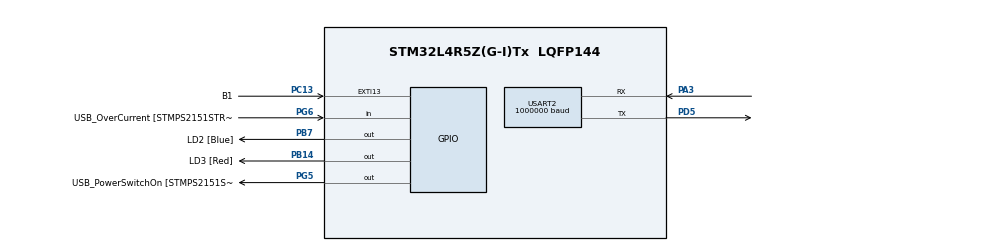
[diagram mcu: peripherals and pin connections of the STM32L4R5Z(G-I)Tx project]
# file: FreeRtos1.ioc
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FREERTOS.INCLUDE_vTaskDelayUntil=1
FREERTOS.Tasks01=defaultTask,0,128,StartDefaultTask,Default,NULL,Dynamic,NULL,NULL
FREERTOS.configTOTAL_HEAP_SIZE=15000
FREERTOS.configUSE_COUNTING_SEMAPHORES=1
FREERTOS.configUSE_RECURSIVE_MUTEXES=1
Mcu.Family=STM32L4
Mcu.Name=STM32L4R5Z(G-I)Tx
Mcu.Package=LQFP144
NVIC.PriorityGroup=NVIC_PRIORITYGROUP_4
NVIC.RCC_IRQn=true\:5\:0\:false\:false\:true\:true\:true
NVIC.TIM1_UP_TIM16_IRQn=true\:0\:0\:false\:false\:true\:false\:false
NVIC.TimeBase=TIM1_UP_TIM16_IRQn
NVIC.TimeBaseIP=TIM1
NVIC.USART2_IRQn=true\:5\:0\:false\:true\:true\:2\:true\:true
PA10.GPIO_Label=USB_ID
PA10.Signal=USB_OTG_FS_ID
PA11.GPIO_Label=USB_DM
PA11.Signal=USB_OTG_FS_DM
PA12.GPIO_Label=USB_DP
PA12.Signal=USB_OTG_FS_DP
PA13\ (JTMS/SWDIO).GPIO_Label=TMS
PA13\ (JTMS/SWDIO).Mode=Trace_Asynchronous_SW
PA13\ (JTMS/SWDIO).Signal=SYS_JTMS-SWDIO
PA14\ (JTCK/SWCLK).GPIO_Label=TCK
PA14\ (JTCK/SWCLK).Mode=Trace_Asynchronous_SW
PA14\ (JTCK/SWCLK).Signal=SYS_JTCK-SWCLK
PA3.GPIO_PuPd=GPIO_PULLUP
PA3.Mode=Asynchronous
PA3.Signal=USART2_RX
PA8.GPIO_Label=USB_SOF [TP1]
PA8.Signal=USB_OTG_FS_SOF
PA9.GPIO_Label=USB_VBUS
PA9.Signal=USB_OTG_FS_VBUS
PB14.GPIO_Label=LD3 [Red]
PB14.PinState=GPIO_PIN_SET
PB14.Signal=GPIO_Output
PB3\ (JTDO/TRACESWO).GPIO_Label=SWO
PB3\ (JTDO/TRACESWO).Mode=Trace_Asynchronous_SW
PB3\ (JTDO/TRACESWO).Signal=SYS_JTDO-SWO
PB7.GPIO_Label=LD2 [Blue]
PB7.Signal=GPIO_Output
PC13.GPIO_Label=B1
PC13.Signal=GPXTI13
PC14-OSC32_IN\ (PC14).Mode=LSE-External-Oscillator
PC14-OSC32_IN\ (PC14).Signal=RCC_OSC32_IN
PC15-OSC32_OUT\ (PC15).Mode=LSE-External-Oscillator
PC15-OSC32_OUT\ (PC15).Signal=RCC_OSC32_OUT
PD5.GPIO_PuPd=GPIO_PULLUP
PD5.Mode=Asynchronous
PD5.Signal=USART2_TX
PD8.GPIO_Label=STLK_RX [STM32F103CBT6_PA3]
PD8.Signal=USART3_TX
PD9.GPIO_Label=STLK_TX [STM32F103CBT6_PA2]
PD9.Signal=USART3_RX
PG5.GPIO_Label=USB_PowerSwitchOn [STMPS2151STR_EN]
PG5.Signal=GPIO_Output
PG6.GPIO_Label=USB_OverCurrent [STMPS2151STR_FAULT]
PG6.Signal=GPIO_Input
PG7.GPIO_Label=STLINK_TX
PG7.Signal=LPUART1_TX
PG8.GPIO_Label=STLINK_RX
PG8.Signal=LPUART1_RX
PH0-OSC_IN\ (PH0).Mode=HSE-External-Oscillator
PH0-OSC_IN\ (PH0).Signal=RCC_OSC_IN
PH1-OSC_OUT\ (PH1).Mode=HSE-External-Oscillator
PH1-OSC_OUT\ (PH1).Signal=RCC_OSC_OUT
ProjectManager.HeapSize=0x200
ProjectManager.StackSize=0x400
ProjectManager.TargetToolchain=SW4STM32
RCC.48MHZClocksFreq_Value=24000000
RCC.ADCFreq_Value=192000000
RCC.AHBFreq_Value=120000000
RCC.APB1CLKDivider=RCC_HCLK_DIV2
RCC.APB1Freq_Value=60000000
RCC.APB1TimFreq_Value=120000000
RCC.APB2Freq_Value=120000000
RCC.APB2TimFreq_Value=120000000
RCC.CK48CLockSelection=RCC_USBCLKSOURCE_MSI
RCC.CortexFreq_Value=120000000
RCC.HCLKFreq_Value=120000000
RCC.HSE_VALUE=48000000
RCC.HSI48_VALUE=48000000
RCC.HSI_VALUE=16000000
RCC.MSIClockRange=RCC_MSIRANGE_11
RCC.MSI_VALUE=48000000
RCC.PLLM1=6
RCC.PLLMUL=RCC_PLL_MUL9
RCC.PLLN=30
RCC.PLLSAI1Q=RCC_PLLQ_DIV4
RCC.PRESCALERUSB=RCC_USBCLKSOURCE_PLL_DIV1_5
RCC.SYSCLKFreq_VALUE=120000000
RCC.SYSCLKSource=RCC_SYSCLKSOURCE_PLLCLK
RCC.SYSCLKSourceVirtual=RCC_SYSCLKSOURCE_PLLCLK
RCC.USBFreq_Value=48000000
RCC.VCOOutputFreq_Value=240000000
USART2.BaudRate=1000000
USART2.SwapParam=ADVFEATURE_SWAP_DISABLE
USART2.VirtualMode-Asynchronous=VM_ASYNC
USART2.WordLength=WORDLENGTH_8B
VP_FREERTOS_VS_ENABLE.Mode=Enabled
VP_RCC_LSE.Mode=CRS SYNC Source LSE
VP_SYS_VS_tim1.Mode=TIM1
board=NUCLEO-L4R5ZI

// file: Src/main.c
/**
  ******************************************************************************
  * @file           : main.c
  * @brief          : Main program body
  ******************************************************************************
  * This notice applies to any and all portions of this file
  * that are not between comment pairs USER CODE BEGIN and
  * USER CODE END. Other portions of this file, whether
  * inserted by the user or by software development tools
  * are owned by their respective copyright owners.
  *
  * Copyright (c) 2018 STMicroelectronics International N.V.
  * All rights reserved.
  *
  * Redistribution and use in source and binary forms, with or without
  * modification, are permitted, provided that the following conditions are met:
  *
  * 1. Redistribution of source code must retain the above copyright notice,
  *    this list of conditions and the following disclaimer.
  * 2. Redistributions in binary form must reproduce the above copyright notice,
  *    this list of conditions and the following disclaimer in the documentation
  *    and/or other materials provided with the distribution.
  * 3. Neither the name of STMicroelectronics nor the names of other
  *    contributors to this software may be used to endorse or promote products
  *    derived from this software without specific written permission.
  * 4. This software, including modifications and/or derivative works of this
  *    software, must execute solely and exclusively on microcontroller or
  *    microprocessor devices manufactured by or for STMicroelectronics.
  * 5. Redistribution and use of this software other than as permitted under
  *    this license is void and will automatically terminate your rights under
  *    this license.
  *
  * THIS SOFTWARE IS PROVIDED BY STMICROELECTRONICS AND CONTRIBUTORS "AS IS"
  * AND ANY EXPRESS, IMPLIED OR STATUTORY WARRANTIES, INCLUDING, BUT NOT
  * LIMITED TO, THE IMPLIED WARRANTIES OF MERCHANTABILITY, FITNESS FOR A
  * PARTICULAR PURPOSE AND NON-INFRINGEMENT OF THIRD PARTY INTELLECTUAL PROPERTY
  * RIGHTS ARE DISCLAIMED TO THE FULLEST EXTENT PERMITTED BY LAW. IN NO EVENT
  * SHALL STMICROELECTRONICS OR CONTRIBUTORS BE LIABLE FOR ANY DIRECT, INDIRECT,
  * INCIDENTAL, SPECIAL, EXEMPLARY, OR CONSEQUENTIAL DAMAGES (INCLUDING, BUT NOT
  * LIMITED TO, PROCUREMENT OF SUBSTITUTE GOODS OR SERVICES; LOSS OF USE, DATA,
  * OR PROFITS; OR BUSINESS INTERRUPTION) HOWEVER CAUSED AND ON ANY THEORY OF
  * LIABILITY, WHETHER IN CONTRACT, STRICT LIABILITY, OR TORT (INCLUDING
  * NEGLIGENCE OR OTHERWISE) ARISING IN ANY WAY OUT OF THE USE OF THIS SOFTWARE,
  * EVEN IF ADVISED OF THE POSSIBILITY OF SUCH DAMAGE.
  *
  ******************************************************************************
  */
#include "main.h"
#include "stm32l4xx_hal.h"
#include "cmsis_os.h"

/* USER CODE BEGIN Includes */
#include "stm32l4xx_nucleo_144.h"
#include "selfFIFO.h"
#include <stdlib.h>
/* USER CODE END Includes */

UART_HandleTypeDef huart2;

osThreadId defaultTaskHandle;

/* USER CODE BEGIN PV */
/* Private variables ---------------------------------------------------------*/

osThreadId TempReadTaskHandle;
osThreadId HumidityReadTaskHandle;
osThreadId dataCaptureTaskHandle;

osMessageQId infoQueueHandle;
osSemaphoreId triggerSemaphore;//
osMutexId lcdMutex;

/* USER CODE END PV */

void SystemClock_Config(void);
static void MX_GPIO_Init(void);
static void MX_USART2_UART_Init(void);
void StartDefaultTask(void const * argument);
static void MX_NVIC_Init(void);

/* USER CODE BEGIN PFP */
/* Private function prototypes -----------------------------------------------*/

static void MX_NVIC_Init(void);

void TempReadTask(); // The temperature will be read every 2secs and displayed/written in a Queue towards the data Capture Task
void HumidityReadTask(); // The humidity will be read every 2secs and displayed/written in a Queue towards the data Capture Task
void dataCaptureTask();// The data will be saved in this task

// Tracesniffer Test: The functions arent implemented
int readTemp();    //Reads the temp // Displayed with flashing of LED3
int readHumidity(); //Reads the temp // Displayed with flashing of LED3
void writeToLCD(); // The LCD is a shared resource// It takes 500ms to write to the LCD // Displayed with LED1
void saveData(); //Data is saved // Displayed by LED2

void uartSendITHandler(UART_HandleTypeDef huart);
void uartReceiveITHandler(UART_HandleTypeDef* huart);
/* USER CODE END PFP */

int main(void)
{

  /* MCU Configuration----------------------------------------------------------*/

  /* Reset of all peripherals, Initializes the Flash interface and the Systick. */
  HAL_Init();

  /* Configure the system clock */
  SystemClock_Config();

  /* Initialize all configured peripherals */
  MX_GPIO_Init();
  MX_USART2_UART_Init();

  /* Initialize interrupts */
  MX_NVIC_Init();
  /* USER CODE BEGIN 2 */
  initialiseTraceSniffer();

  osMessageQDef(infoQueueHandle, 10, int);
  infoQueueHandle = osMessageCreate(osMessageQ(infoQueueHandle), NULL);
  /* USER CODE END 2 */

  /* USER CODE BEGIN RTOS_MUTEX */

  lcdMutex=xSemaphoreCreateMutex();
  /* USER CODE END RTOS_MUTEX */

  /* USER CODE BEGIN RTOS_SEMAPHORES */
  triggerSemaphore=xSemaphoreCreateCounting(5,0);
  /* USER CODE END RTOS_SEMAPHORES */

  /* Create the thread(s) */
  /* definition and creation of defaultTask */
 // osThreadDef(defaultTask, StartDefaultTask, osPriorityNormal, 0, 128);
  //defaultTaskHandle = osThreadCreate(osThread(defaultTask), NULL);

  /* USER CODE BEGIN RTOS_THREADS */
  /* add threads, ... */
  osThreadDef(humid, HumidityReadTask, osPriorityBelowNormal, 0, 128);
  HumidityReadTaskHandle = osThreadCreate(osThread(humid), NULL);

  osThreadDef(temp, TempReadTask, osPriorityNormal, 0, 128);
  TempReadTaskHandle = osThreadCreate(osThread(temp), NULL);

  osThreadDef(data, dataCaptureTask, osPriorityAboveNormal, 0, 128);
  dataCaptureTaskHandle = osThreadCreate(osThread(data), NULL);
  /* USER CODE END RTOS_THREADS */

  /* Start scheduler */
  osKernelStart();

  /* We should never get here as control is now taken by the scheduler */

  /* Infinite loop */
  while (1)
  {

  }

}

void SystemClock_Config(void)
{

  RCC_OscInitTypeDef RCC_OscInitStruct;
  RCC_ClkInitTypeDef RCC_ClkInitStruct;
  RCC_PeriphCLKInitTypeDef PeriphClkInit;
  RCC_CRSInitTypeDef RCC_CRSInitStruct;

    /**Configure the main internal regulator output voltage
    */
  if (HAL_PWREx_ControlVoltageScaling(PWR_REGULATOR_VOLTAGE_SCALE1_BOOST) != HAL_OK)
  {
    _Error_Handler(__FILE__, __LINE__);
  }

    /**Configure LSE Drive Capability
    */
  __HAL_RCC_LSEDRIVE_CONFIG(RCC_LSEDRIVE_LOW);

    /**Initializes the CPU, AHB and APB busses clocks
    */
  RCC_OscInitStruct.OscillatorType = RCC_OSCILLATORTYPE_HSI48|RCC_OSCILLATORTYPE_LSE
                              |RCC_OSCILLATORTYPE_MSI;
  RCC_OscInitStruct.LSEState = RCC_LSE_ON;
  RCC_OscInitStruct.HSI48State = RCC_HSI48_ON;
  RCC_OscInitStruct.MSIState = RCC_MSI_ON;
  RCC_OscInitStruct.MSICalibrationValue = 0;
  RCC_OscInitStruct.MSIClockRange = RCC_MSIRANGE_11;
  RCC_OscInitStruct.PLL.PLLState = RCC_PLL_ON;
  RCC_OscInitStruct.PLL.PLLSource = RCC_PLLSOURCE_MSI;
  RCC_OscInitStruct.PLL.PLLN = 30;
  RCC_OscInitStruct.PLL.PLLP = RCC_PLLP_DIV2;
  RCC_OscInitStruct.PLL.PLLQ = RCC_PLLQ_DIV2;
  RCC_OscInitStruct.PLL.PLLR = RCC_PLLR_DIV2;
  if (HAL_RCC_OscConfig(&RCC_OscInitStruct) != HAL_OK)
  {
    _Error_Handler(__FILE__, __LINE__);
  }

    /**Initializes the CPU, AHB and APB busses clocks
    */
  RCC_ClkInitStruct.ClockType = RCC_CLOCKTYPE_HCLK|RCC_CLOCKTYPE_SYSCLK
                              |RCC_CLOCKTYPE_PCLK1|RCC_CLOCKTYPE_PCLK2;
  RCC_ClkInitStruct.SYSCLKSource = RCC_SYSCLKSOURCE_PLLCLK;
  RCC_ClkInitStruct.AHBCLKDivider = RCC_SYSCLK_DIV1;
  RCC_ClkInitStruct.APB1CLKDivider = RCC_HCLK_DIV2;
  RCC_ClkInitStruct.APB2CLKDivider = RCC_HCLK_DIV1;

  if (HAL_RCC_ClockConfig(&RCC_ClkInitStruct, FLASH_LATENCY_5) != HAL_OK)
  {
    _Error_Handler(__FILE__, __LINE__);
  }

  PeriphClkInit.PeriphClockSelection = RCC_PERIPHCLK_USART2;
  PeriphClkInit.Usart2ClockSelection = RCC_USART2CLKSOURCE_PCLK1;
  if (HAL_RCCEx_PeriphCLKConfig(&PeriphClkInit) != HAL_OK)
  {
    _Error_Handler(__FILE__, __LINE__);
  }

    /**Configure the Systick interrupt time
    */
  HAL_SYSTICK_Config(HAL_RCC_GetHCLKFreq()/1000);

    /**Configure the Systick
    */
  HAL_SYSTICK_CLKSourceConfig(SYSTICK_CLKSOURCE_HCLK);

    /**Enable MSI Auto calibration
    */
  HAL_RCCEx_EnableMSIPLLMode();

    /**Enable the SYSCFG APB clock
    */
  __HAL_RCC_CRS_CLK_ENABLE();

    /**Configures CRS
    */
  RCC_CRSInitStruct.Prescaler = RCC_CRS_SYNC_DIV1;
  RCC_CRSInitStruct.Source = RCC_CRS_SYNC_SOURCE_LSE;
  RCC_CRSInitStruct.Polarity = RCC_CRS_SYNC_POLARITY_RISING;
  RCC_CRSInitStruct.ReloadValue = __HAL_RCC_CRS_RELOADVALUE_CALCULATE(48000000,32768);
  RCC_CRSInitStruct.ErrorLimitValue = 34;
  RCC_CRSInitStruct.HSI48CalibrationValue = 32;

  HAL_RCCEx_CRSConfig(&RCC_CRSInitStruct);

  /* SysTick_IRQn interrupt configuration */
  HAL_NVIC_SetPriority(SysTick_IRQn, 15, 0);
}

/**
  * @brief NVIC Configuration.
  * @retval None
  */
static void MX_NVIC_Init(void)
{
  /* USART2_IRQn interrupt configuration */
  HAL_NVIC_SetPriority(USART2_IRQn, 5, 0);
  HAL_NVIC_EnableIRQ(USART2_IRQn);
}

/* USART2 init function */
static void MX_USART2_UART_Init(void)
{

  huart2.Instance = USART2;
  huart2.Init.BaudRate = 1000000;
  huart2.Init.WordLength = UART_WORDLENGTH_8B;
  huart2.Init.StopBits = UART_STOPBITS_1;
  huart2.Init.Parity = UART_PARITY_NONE;
  huart2.Init.Mode = UART_MODE_TX_RX;
  huart2.Init.HwFlowCtl = UART_HWCONTROL_NONE;
  huart2.Init.OverSampling = UART_OVERSAMPLING_16;
  huart2.Init.OneBitSampling = UART_ONE_BIT_SAMPLE_DISABLE;
  huart2.Init.ClockPrescaler = UART_PRESCALER_DIV1;
  huart2.AdvancedInit.AdvFeatureInit = UART_ADVFEATURE_NO_INIT;
  if (HAL_UART_Init(&huart2) != HAL_OK)
  {
    _Error_Handler(__FILE__, __LINE__);
  }

  if (HAL_UARTEx_SetTxFifoThreshold(&huart2, UART_TXFIFO_THRESHOLD_1_8) != HAL_OK)
  {
    _Error_Handler(__FILE__, __LINE__);
  }

  if (HAL_UARTEx_SetRxFifoThreshold(&huart2, UART_RXFIFO_THRESHOLD_1_8) != HAL_OK)
  {
    _Error_Handler(__FILE__, __LINE__);
  }

  if (HAL_UARTEx_DisableFifoMode(&huart2) != HAL_OK)
  {
    _Error_Handler(__FILE__, __LINE__);
  }

}

/** Configure pins as
        * Analog
        * Input
        * Output
        * EVENT_OUT
        * EXTI
        * Free pins are configured automatically as Analog (this feature is enabled through
        * the Code Generation settings)
     PD8   ------> USART3_TX
     PD9   ------> USART3_RX
     PG7   ------> LPUART1_TX
     PG8   ------> LPUART1_RX
     PA8   ------> USB_OTG_FS_SOF
     PA9   ------> USB_OTG_FS_VBUS
     PA10   ------> USB_OTG_FS_ID
     PA11   ------> USB_OTG_FS_DM
     PA12   ------> USB_OTG_FS_DP
*/
static void MX_GPIO_Init(void)
{

  GPIO_InitTypeDef GPIO_InitStruct;

  /* GPIO Ports Clock Enable */
  __HAL_RCC_GPIOE_CLK_ENABLE();
  __HAL_RCC_GPIOC_CLK_ENABLE();
  __HAL_RCC_GPIOF_CLK_ENABLE();
  __HAL_RCC_GPIOH_CLK_ENABLE();
  __HAL_RCC_GPIOA_CLK_ENABLE();
  __HAL_RCC_GPIOB_CLK_ENABLE();
  __HAL_RCC_GPIOG_CLK_ENABLE();
  __HAL_RCC_GPIOD_CLK_ENABLE();
  HAL_PWREx_EnableVddIO2();

  /*Configure GPIO pin Output Level */
  HAL_GPIO_WritePin(LD3_GPIO_Port, LD3_Pin, GPIO_PIN_RESET);

  /*Configure GPIO pin Output Level */
  HAL_GPIO_WritePin(USB_PowerSwitchOn_GPIO_Port, USB_PowerSwitchOn_Pin, GPIO_PIN_RESET);

  /*Configure GPIO pin Output Level */
  HAL_GPIO_WritePin(LD2_GPIO_Port, LD2_Pin, GPIO_PIN_RESET);

  /*Configure GPIO pins : PE2 PE3 PE4 PE5
                           PE6 PE7 PE8 PE9
                           PE10 PE11 PE12 PE13
                           PE14 PE15 PE0 PE1 */
  GPIO_InitStruct.Pin = GPIO_PIN_2|GPIO_PIN_3|GPIO_PIN_4|GPIO_PIN_5
                          |GPIO_PIN_6|GPIO_PIN_7|GPIO_PIN_8|GPIO_PIN_9
                          |GPIO_PIN_10|GPIO_PIN_11|GPIO_PIN_12|GPIO_PIN_13
                          |GPIO_PIN_14|GPIO_PIN_15|GPIO_PIN_0|GPIO_PIN_1;
  GPIO_InitStruct.Mode = GPIO_MODE_ANALOG;
  GPIO_InitStruct.Pull = GPIO_NOPULL;
  HAL_GPIO_Init(GPIOE, &GPIO_InitStruct);

  /*Configure GPIO pin : B1_Pin */
  GPIO_InitStruct.Pin = B1_Pin;
  GPIO_InitStruct.Mode = GPIO_MODE_IT_RISING;
  GPIO_InitStruct.Pull = GPIO_NOPULL;
  HAL_GPIO_Init(B1_GPIO_Port, &GPIO_InitStruct);

  /*Configure GPIO pins : PF0 PF1 PF2 PF3
                           PF4 PF5 PF6 PF7
                           PF8 PF9 PF10 PF11
                           PF12 PF13 PF14 PF15 */
  GPIO_InitStruct.Pin = GPIO_PIN_0|GPIO_PIN_1|GPIO_PIN_2|GPIO_PIN_3
                          |GPIO_PIN_4|GPIO_PIN_5|GPIO_PIN_6|GPIO_PIN_7
                          |GPIO_PIN_8|GPIO_PIN_9|GPIO_PIN_10|GPIO_PIN_11
                          |GPIO_PIN_12|GPIO_PIN_13|GPIO_PIN_14|GPIO_PIN_15;
  GPIO_InitStruct.Mode = GPIO_MODE_ANALOG;
  GPIO_InitStruct.Pull = GPIO_NOPULL;
  HAL_GPIO_Init(GPIOF, &GPIO_InitStruct);

  /*Configure GPIO pins : PC0 PC1 PC2 PC3
                           PC4 PC5 PC6 PC7
                           PC8 PC9 PC10 PC11
                           PC12 */
  GPIO_InitStruct.Pin = GPIO_PIN_0|GPIO_PIN_1|GPIO_PIN_2|GPIO_PIN_3
                          |GPIO_PIN_4|GPIO_PIN_5|GPIO_PIN_6|GPIO_PIN_7
                          |GPIO_PIN_8|GPIO_PIN_9|GPIO_PIN_10|GPIO_PIN_11
                          |GPIO_PIN_12;
  GPIO_InitStruct.Mode = GPIO_MODE_ANALOG;
  GPIO_InitStruct.Pull = GPIO_NOPULL;
  HAL_GPIO_Init(GPIOC, &GPIO_InitStruct);

  /*Configure GPIO pins : PA0 PA1 PA2 PA4
                           PA5 PA6 PA7 PA15 */
  GPIO_InitStruct.Pin = GPIO_PIN_0|GPIO_PIN_1|GPIO_PIN_2|GPIO_PIN_4
                          |GPIO_PIN_5|GPIO_PIN_6|GPIO_PIN_7|GPIO_PIN_15;
  GPIO_InitStruct.Mode = GPIO_MODE_ANALOG;
  GPIO_InitStruct.Pull = GPIO_NOPULL;
  HAL_GPIO_Init(GPIOA, &GPIO_InitStruct);

  /*Configure GPIO pins : PB0 PB1 PB2 PB10
                           PB11 PB12 PB13 PB15
                           PB4 PB5 PB6 PB8
                           PB9 */
  GPIO_InitStruct.Pin = GPIO_PIN_0|GPIO_PIN_1|GPIO_PIN_2|GPIO_PIN_10
                          |GPIO_PIN_11|GPIO_PIN_12|GPIO_PIN_13|GPIO_PIN_15
                          |GPIO_PIN_4|GPIO_PIN_5|GPIO_PIN_6|GPIO_PIN_8
                          |GPIO_PIN_9;
  GPIO_InitStruct.Mode = GPIO_MODE_ANALOG;
  GPIO_InitStruct.Pull = GPIO_NOPULL;
  HAL_GPIO_Init(GPIOB, &GPIO_InitStruct);

  /*Configure GPIO pins : PG0 PG1 PG2 PG3
                           PG4 PG9 PG10 PG11
                           PG12 PG13 PG14 PG15 */
  GPIO_InitStruct.Pin = GPIO_PIN_0|GPIO_PIN_1|GPIO_PIN_2|GPIO_PIN_3
                          |GPIO_PIN_4|GPIO_PIN_9|GPIO_PIN_10|GPIO_PIN_11
                          |GPIO_PIN_12|GPIO_PIN_13|GPIO_PIN_14|GPIO_PIN_15;
  GPIO_InitStruct.Mode = GPIO_MODE_ANALOG;
  GPIO_InitStruct.Pull = GPIO_NOPULL;
  HAL_GPIO_Init(GPIOG, &GPIO_InitStruct);

  /*Configure GPIO pins : LD3_Pin LD2_Pin */
  GPIO_InitStruct.Pin = LD3_Pin|LD2_Pin;
  GPIO_InitStruct.Mode = GPIO_MODE_OUTPUT_PP;
  GPIO_InitStruct.Pull = GPIO_NOPULL;
  GPIO_InitStruct.Speed = GPIO_SPEED_FREQ_LOW;
  HAL_GPIO_Init(GPIOB, &GPIO_InitStruct);

  /*Configure GPIO pins : STLK_RX_Pin STLK_TX_Pin */
  GPIO_InitStruct.Pin = STLK_RX_Pin|STLK_TX_Pin;
  GPIO_InitStruct.Mode = GPIO_MODE_AF_PP;
  GPIO_InitStruct.Pull = GPIO_NOPULL;
  GPIO_InitStruct.Speed = GPIO_SPEED_FREQ_VERY_HIGH;
  GPIO_InitStruct.Alternate = GPIO_AF7_USART3;
  HAL_GPIO_Init(GPIOD, &GPIO_InitStruct);

  /*Configure GPIO pins : PD10 PD11 PD12 PD13
                           PD14 PD15 PD0 PD1
                           PD2 PD3 PD4 PD6
                           PD7 */
  GPIO_InitStruct.Pin = GPIO_PIN_10|GPIO_PIN_11|GPIO_PIN_12|GPIO_PIN_13
                          |GPIO_PIN_14|GPIO_PIN_15|GPIO_PIN_0|GPIO_PIN_1
                          |GPIO_PIN_2|GPIO_PIN_3|GPIO_PIN_4|GPIO_PIN_6
                          |GPIO_PIN_7;
  GPIO_InitStruct.Mode = GPIO_MODE_ANALOG;
  GPIO_InitStruct.Pull = GPIO_NOPULL;
  HAL_GPIO_Init(GPIOD, &GPIO_InitStruct);

  /*Configure GPIO pin : USB_PowerSwitchOn_Pin */
  GPIO_InitStruct.Pin = USB_PowerSwitchOn_Pin;
  GPIO_InitStruct.Mode = GPIO_MODE_OUTPUT_PP;
  GPIO_InitStruct.Pull = GPIO_NOPULL;
  GPIO_InitStruct.Speed = GPIO_SPEED_FREQ_LOW;
  HAL_GPIO_Init(USB_PowerSwitchOn_GPIO_Port, &GPIO_InitStruct);

  /*Configure GPIO pin : USB_OverCurrent_Pin */
  GPIO_InitStruct.Pin = USB_OverCurrent_Pin;
  GPIO_InitStruct.Mode = GPIO_MODE_INPUT;
  GPIO_InitStruct.Pull = GPIO_NOPULL;
  HAL_GPIO_Init(USB_OverCurrent_GPIO_Port, &GPIO_InitStruct);

  /*Configure GPIO pins : STLINK_TX_Pin STLINK_RX_Pin */
  GPIO_InitStruct.Pin = STLINK_TX_Pin|STLINK_RX_Pin;
  GPIO_InitStruct.Mode = GPIO_MODE_AF_PP;
  GPIO_InitStruct.Pull = GPIO_NOPULL;
  GPIO_InitStruct.Speed = GPIO_SPEED_FREQ_VERY_HIGH;
  GPIO_InitStruct.Alternate = GPIO_AF8_LPUART1;
  HAL_GPIO_Init(GPIOG, &GPIO_InitStruct);

  /*Configure GPIO pins : USB_SOF_Pin USB_ID_Pin USB_DM_Pin USB_DP_Pin */
  GPIO_InitStruct.Pin = USB_SOF_Pin|USB_ID_Pin|USB_DM_Pin|USB_DP_Pin;
  GPIO_InitStruct.Mode = GPIO_MODE_AF_PP;
  GPIO_InitStruct.Pull = GPIO_NOPULL;
  GPIO_InitStruct.Speed = GPIO_SPEED_FREQ_VERY_HIGH;
  GPIO_InitStruct.Alternate = GPIO_AF10_OTG_FS;
  HAL_GPIO_Init(GPIOA, &GPIO_InitStruct);

  /*Configure GPIO pin : USB_VBUS_Pin */
  GPIO_InitStruct.Pin = USB_VBUS_Pin;
  GPIO_InitStruct.Mode = GPIO_MODE_INPUT;
  GPIO_InitStruct.Pull = GPIO_NOPULL;
  HAL_GPIO_Init(USB_VBUS_GPIO_Port, &GPIO_InitStruct);

  /*Configure GPIO pin : PH3 */
  GPIO_InitStruct.Pin = GPIO_PIN_3;
  GPIO_InitStruct.Mode = GPIO_MODE_ANALOG;
  GPIO_InitStruct.Pull = GPIO_NOPULL;
  HAL_GPIO_Init(GPIOH, &GPIO_InitStruct);

}

/* USER CODE BEGIN 4 */

void uartReceiveITHandler(UART_HandleTypeDef* huart)
{
	uint8_t data;
	//HAL_UART_Receive(&huart,&data,1,0);
	data = READ_REG(huart->Instance->RDR);
	//HAL_UART_Receive_IT(huart,&data,1);
	sendReceivedByteToSniffTask(data);

}

void uartSendITHandler(UART_HandleTypeDef huart)
{
	uint8_t msg =0;
	if(BufferOut(&msg)==BUFFER_SUCCESS)
	{
		huart.Instance->TDR=(msg & (uint8_t)0xFFU);
	}
	else{

		CLEAR_BIT(huart.Instance->CR1, USART_CR1_TXEIE_TXFNFIE);

	}

}
int readTemp()    //Reads the temp // Displayed with flashing of LED3
{
	BSP_LED_On(LED3);
	HAL_Delay(50);
	BSP_LED_Off(LED3);
	return rand();
}
int readHumidity() //Reads the humidity // Displayed with flashing of LED3
{
	BSP_LED_On(LED3);
	HAL_Delay(50);
	BSP_LED_Off(LED3);
	return rand();
}

void writeToLCD() // The LCD is a shared resource// It takes 500ms to write to the LCD // Displayed with LED1
{
	BSP_LED_On(LED1);
	HAL_Delay(40);
	BSP_LED_Off(LED1);
	HAL_Delay(50);
}

void saveData() //Data is saved // Displayed by LED2
{
	BSP_LED_On(LED2);
	HAL_Delay(50);
	BSP_LED_Off(LED2);
}
void TempReadTask()
{
	TickType_t lastwoken;
	lastwoken = xTaskGetTickCount();
	int temp;
//	traceCUSTOM_MARKER_1();
	while(1)
	{
		osDelayUntil(&lastwoken,2000);
		temp=readTemp();
		xQueueSend(infoQueueHandle,&temp,portMAX_DELAY);
		if(xSemaphoreTake(lcdMutex,portMAX_DELAY)){
			writeToLCD();
			xSemaphoreGive(lcdMutex);
		}

	}
}
void HumidityReadTask()
{
	TickType_t lastwoken;
	lastwoken = xTaskGetTickCount();
	int humidity;
//	traceCUSTOM_MARKER_2();
	while(1)
	{
		osDelayUntil(&lastwoken,2000);

		//writeFIFO(sniffFifo,&humidity,4,prioRECEIVE);
		//sendObjectList();

		humidity=readHumidity();
		xQueueSend(infoQueueHandle,&humidity,portMAX_DELAY);
		if(xSemaphoreTake(lcdMutex,portMAX_DELAY)){
			writeToLCD();
			xSemaphoreGive(lcdMutex);
		}
	}
}
void dataCaptureTask()
{
	int info;
//	traceCUSTOM_MARKER_3();
	BSP_LED_Init(LED1);
	while(1)
	{
		xQueueReceive(infoQueueHandle,&info,portMAX_DELAY);
		saveData();
	}
}
/* USER CODE END 4 */

/* StartDefaultTask function */
void StartDefaultTask(void const * argument)
{

  for(;;)
  {
    osDelay(1);
  }
}

void HAL_TIM_PeriodElapsedCallback(TIM_HandleTypeDef *htim)
{
  if (htim->Instance == TIM1) {
    HAL_IncTick();
  }
}

void _Error_Handler(char *file, int line)
{
  /* USER CODE BEGIN Error_Handler_Debug */
  /* User can add his own implementation to report the HAL error return state */
  while(1)
  {
	  sendByteOverInterface(255);
  }
  /* USER CODE END Error_Handler_Debug */
}
void Own_HardFault_Handler(char *file, int line)
{
  while(1)
  {
  }
}

/************************ (C) COPYRIGHT STMicroelectronics *****END OF FILE****/
